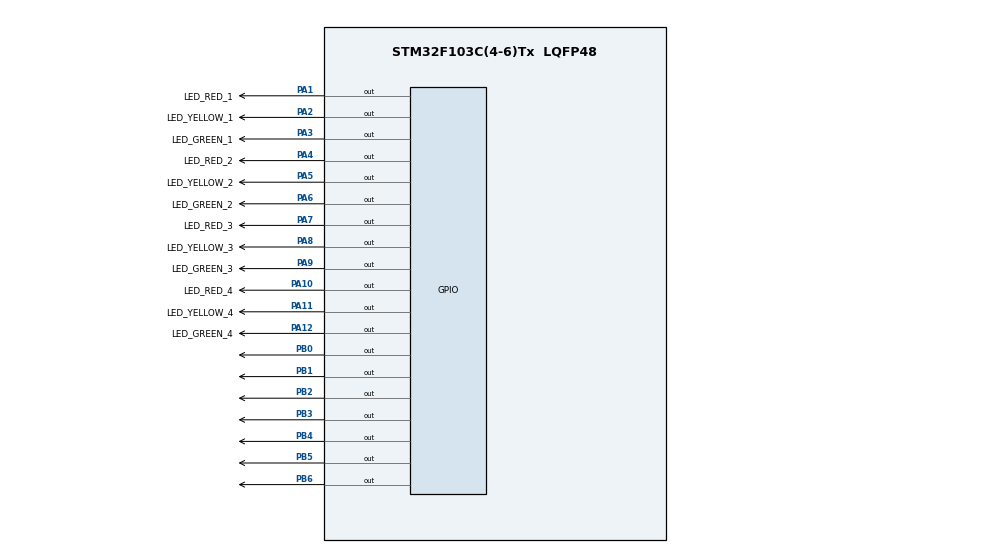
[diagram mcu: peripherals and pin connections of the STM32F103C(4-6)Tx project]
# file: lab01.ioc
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Mcu.Family=STM32F1
Mcu.Name=STM32F103C(4-6)Tx
Mcu.Package=LQFP48
NVIC.PriorityGroup=NVIC_PRIORITYGROUP_4
PA1.GPIO_Label=LED_RED_1
PA1.PinState=GPIO_PIN_SET
PA1.Signal=GPIO_Output
PA10.GPIO_Label=LED_RED_4
PA10.PinState=GPIO_PIN_SET
PA10.Signal=GPIO_Output
PA11.GPIO_Label=LED_YELLOW_4
PA11.PinState=GPIO_PIN_SET
PA11.Signal=GPIO_Output
PA12.GPIO_Label=LED_GREEN_4
PA12.PinState=GPIO_PIN_SET
PA12.Signal=GPIO_Output
PA2.GPIO_Label=LED_YELLOW_1
PA2.PinState=GPIO_PIN_SET
PA2.Signal=GPIO_Output
PA3.GPIO_Label=LED_GREEN_1
PA3.PinState=GPIO_PIN_SET
PA3.Signal=GPIO_Output
PA4.GPIO_Label=LED_RED_2
PA4.PinState=GPIO_PIN_SET
PA4.Signal=GPIO_Output
PA5.GPIO_Label=LED_YELLOW_2
PA5.PinState=GPIO_PIN_SET
PA5.Signal=GPIO_Output
PA6.GPIO_Label=LED_GREEN_2
PA6.PinState=GPIO_PIN_SET
PA6.Signal=GPIO_Output
PA7.GPIO_Label=LED_RED_3
PA7.PinState=GPIO_PIN_SET
PA7.Signal=GPIO_Output
PA8.GPIO_Label=LED_YELLOW_3
PA8.PinState=GPIO_PIN_SET
PA8.Signal=GPIO_Output
PA9.GPIO_Label=LED_GREEN_3
PA9.PinState=GPIO_PIN_SET
PA9.Signal=GPIO_Output
PB0.PinState=GPIO_PIN_SET
PB0.Signal=GPIO_Output
PB1.PinState=GPIO_PIN_SET
PB1.Signal=GPIO_Output
PB2.PinState=GPIO_PIN_SET
PB2.Signal=GPIO_Output
PB3.PinState=GPIO_PIN_SET
PB3.Signal=GPIO_Output
PB4.PinState=GPIO_PIN_SET
PB4.Signal=GPIO_Output
PB5.PinState=GPIO_PIN_SET
PB5.Signal=GPIO_Output
PB6.PinState=GPIO_PIN_SET
PB6.Signal=GPIO_Output
ProjectManager.HeapSize=0x200
ProjectManager.StackSize=0x400
ProjectManager.TargetToolchain=STM32CubeIDE
RCC.APB1Freq_Value=8000000
RCC.APB2Freq_Value=8000000
board=custom

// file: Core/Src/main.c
/* USER CODE BEGIN Header */
/**
  ******************************************************************************
  * @file           : main.c
  * @brief          : Main program body
  ******************************************************************************
  * @attention
  *
  * Copyright (c) 2025 STMicroelectronics.
  * All rights reserved.
  *
  * This software is licensed under terms that can be found in the LICENSE file
  * in the root directory of this software component.
  * If no LICENSE file comes with this software, it is provided AS-IS.
  *
  ******************************************************************************
  */
/* USER CODE END Header */
#include "main.h"

/* USER CODE BEGIN PM */
#define RED_TIMER 5
#define YELLOW_TIMER 2
#define GREEN_TIMER 3
/* USER CODE END PM */

void SystemClock_Config(void);
static void MX_GPIO_Init(void);

int main(void)
{

  /* MCU Configuration--------------------------------------------------------*/

  /* Reset of all peripherals, Initializes the Flash interface and the Systick. */
  HAL_Init();

  /* Configure the system clock */
  SystemClock_Config();

  /* Initialize all configured peripherals */
  MX_GPIO_Init();
  /* USER CODE BEGIN 2 */
  HAL_GPIO_TogglePin(LED_GREEN_GPIO_Port, LED_GREEN_Pin);
  int counter = GREEN_TIMER;
  uint8_t state = 0;	// 2=RED, 1=YELLOW, 0=GREEN
  /* USER CODE END 2 */

  /* Infinite loop */
  /* USER CODE BEGIN WHILE */
  while (1)
  {
	if (counter <= 0)
	{
		if (state == 0)
		{
			HAL_GPIO_TogglePin(LED_GREEN_GPIO_Port, LED_GREEN_Pin);
			HAL_GPIO_TogglePin(LED_YELLOW_GPIO_Port, LED_YELLOW_Pin);

			counter = YELLOW_TIMER;
			state = 1;
		}
		else if (state == 1)
		{
			HAL_GPIO_TogglePin(LED_YELLOW_GPIO_Port, LED_YELLOW_Pin);
			HAL_GPIO_TogglePin(LED_RED_GPIO_Port, LED_RED_Pin);

			counter = RED_TIMER;
			state = 2;
		}
		else
		{
			HAL_GPIO_TogglePin(LED_RED_GPIO_Port, LED_RED_Pin);
			HAL_GPIO_TogglePin(LED_GREEN_GPIO_Port, LED_GREEN_Pin);

			counter = GREEN_TIMER;
			state = 0;
		}
	}
	counter--;
	HAL_Delay(1000);
    /* USER CODE END WHILE */

  }
}

void SystemClock_Config(void)
{
  RCC_OscInitTypeDef RCC_OscInitStruct = {0};
  RCC_ClkInitTypeDef RCC_ClkInitStruct = {0};

  /** Initializes the RCC Oscillators according to the specified parameters
  * in the RCC_OscInitTypeDef structure.
  */
  RCC_OscInitStruct.OscillatorType = RCC_OSCILLATORTYPE_HSI;
  RCC_OscInitStruct.HSIState = RCC_HSI_ON;
  RCC_OscInitStruct.HSICalibrationValue = RCC_HSICALIBRATION_DEFAULT;
  RCC_OscInitStruct.PLL.PLLState = RCC_PLL_NONE;
  if (HAL_RCC_OscConfig(&RCC_OscInitStruct) != HAL_OK)
  {
    Error_Handler();
  }

  /** Initializes the CPU, AHB and APB buses clocks
  */
  RCC_ClkInitStruct.ClockType = RCC_CLOCKTYPE_HCLK|RCC_CLOCKTYPE_SYSCLK
                              |RCC_CLOCKTYPE_PCLK1|RCC_CLOCKTYPE_PCLK2;
  RCC_ClkInitStruct.SYSCLKSource = RCC_SYSCLKSOURCE_HSI;
  RCC_ClkInitStruct.AHBCLKDivider = RCC_SYSCLK_DIV1;
  RCC_ClkInitStruct.APB1CLKDivider = RCC_HCLK_DIV1;
  RCC_ClkInitStruct.APB2CLKDivider = RCC_HCLK_DIV1;

  if (HAL_RCC_ClockConfig(&RCC_ClkInitStruct, FLASH_LATENCY_0) != HAL_OK)
  {
    Error_Handler();
  }
}

static void MX_GPIO_Init(void)
{
  GPIO_InitTypeDef GPIO_InitStruct = {0};

  /* GPIO Ports Clock Enable */
  __HAL_RCC_GPIOA_CLK_ENABLE();

  /*Configure GPIO pin Output Level */
  HAL_GPIO_WritePin(GPIOA, LED_RED_Pin|LED_YELLOW_Pin|LED_GREEN_Pin, GPIO_PIN_SET);

  /*Configure GPIO pins : LED_RED_Pin LED_YELLOW_Pin LED_GREEN_Pin */
  GPIO_InitStruct.Pin = LED_RED_Pin|LED_YELLOW_Pin|LED_GREEN_Pin;
  GPIO_InitStruct.Mode = GPIO_MODE_OUTPUT_PP;
  GPIO_InitStruct.Pull = GPIO_NOPULL;
  GPIO_InitStruct.Speed = GPIO_SPEED_FREQ_LOW;
  HAL_GPIO_Init(GPIOA, &GPIO_InitStruct);

}

void Error_Handler(void)
{
  __disable_irq();
  while (1)
  {
  }
}
